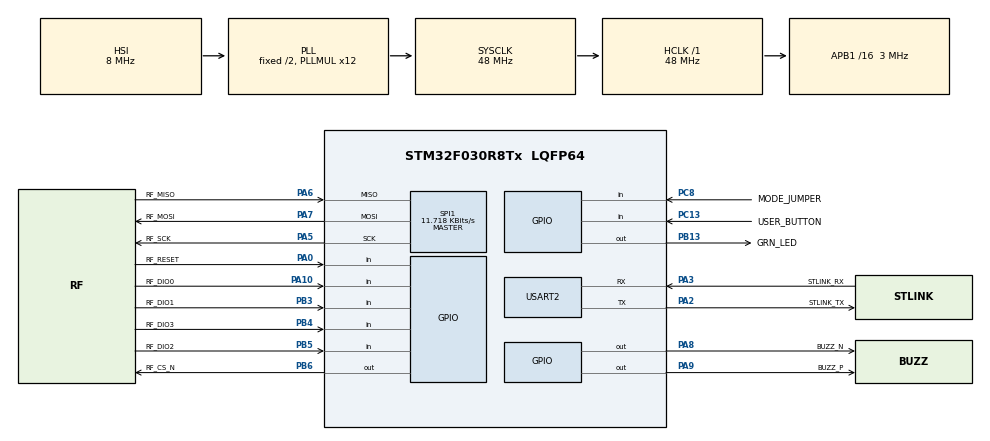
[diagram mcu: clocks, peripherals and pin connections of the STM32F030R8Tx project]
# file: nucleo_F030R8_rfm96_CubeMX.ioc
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Mcu.Family=STM32F0
Mcu.Name=STM32F030R8Tx
Mcu.Package=LQFP64
NVIC.SPI1_IRQn=true\:1\:0\:true\:true\:true\:2\:true\:true
NVIC.USART2_IRQn=true\:2\:0\:true\:true\:true\:1\:true\:true
PA0.GPIO_Label=RF_RESET
PA0.Signal=GPIO_Input
PA10.GPIO_Label=RF_DIO0
PA10.Signal=GPIO_Input
PA13.GPIO_Label=TMS
PA13.Signal=SYS_SWDIO
PA14.GPIO_Label=TCK
PA14.Signal=SYS_SWCLK
PA2.GPIO_Label=STLINK_TX
PA2.GPIO_Mode=GPIO_MODE_AF_PP
PA2.GPIO_PuPd=GPIO_NOPULL
PA2.GPIO_Speed=GPIO_SPEED_FREQ_LOW
PA2.Mode=Asynchronous
PA2.Signal=USART2_TX
PA3.GPIO_Label=STLINK_RX
PA3.GPIO_Mode=GPIO_MODE_AF_PP
PA3.GPIO_PuPd=GPIO_NOPULL
PA3.GPIO_Speed=GPIO_SPEED_FREQ_LOW
PA3.Mode=Asynchronous
PA3.Signal=USART2_RX
PA5.GPIO_Label=RF_SCK
PA5.Mode=Full_Duplex_Master
PA5.Signal=SPI1_SCK
PA6.GPIO_Label=RF_MISO
PA6.Mode=Full_Duplex_Master
PA6.Signal=SPI1_MISO
PA7.GPIO_Label=RF_MOSI
PA7.Mode=Full_Duplex_Master
PA7.Signal=SPI1_MOSI
PA8.GPIO_Label=BUZZ_N
PA8.Signal=GPIO_Output
PA9.GPIO_Label=BUZZ_P
PA9.Signal=GPIO_Output
PB13.GPIO_Label=GRN_LED
PB13.Signal=GPIO_Output
PB3.GPIO_Label=RF_DIO1
PB3.Signal=GPIO_Input
PB4.GPIO_Label=RF_DIO3
PB4.Signal=GPIO_Input
PB5.GPIO_Label=RF_DIO2
PB5.Signal=GPIO_Input
PB6.GPIO_Label=RF_CS_N
PB6.GPIO_Speed=GPIO_SPEED_FREQ_MEDIUM
PB6.PinState=GPIO_PIN_SET
PB6.Signal=GPIO_Output
PC13.GPIO_Label=USER_BUTTON
PC13.Signal=GPIO_Input
PC14-OSC32_IN.Mode=LSE-External-Oscillator
PC14-OSC32_IN.Signal=RCC_OSC32_IN
PC15-OSC32_OUT.Mode=LSE-External-Oscillator
PC15-OSC32_OUT.Signal=RCC_OSC32_OUT
PC8.GPIO_Label=MODE_JUMPER
PC8.GPIO_PuPd=GPIO_PULLUP
PC8.Signal=GPIO_Input
PF0-OSC_IN.Mode=HSE-External-Clock-Source
PF0-OSC_IN.Signal=RCC_OSC_IN
PF1-OSC_OUT.Signal=RCC_OSC_OUT
ProjectManager.HeapSize=0x200
ProjectManager.StackSize=0x400
ProjectManager.TargetToolchain=SW4STM32
RCC.AHBFreq_Value=48000000
RCC.APB1CLKDivider=RCC_HCLK_DIV16
RCC.APB1Freq_Value=3000000
RCC.APB1TimFreq_Value=6000000
RCC.HCLKFreq_Value=48000000
RCC.PLLMUL=RCC_PLL_MUL12
RCC.SYSCLKFreq_VALUE=48000000
RCC.SYSCLKSource=RCC_SYSCLKSOURCE_PLLCLK
SPI1.BaudRatePrescaler=SPI_BAUDRATEPRESCALER_256
SPI1.CalculateBaudRate=11.718 KBits/s
SPI1.DataSize=SPI_DATASIZE_8BIT
SPI1.Direction=SPI_DIRECTION_2LINES
SPI1.Mode=SPI_MODE_MASTER
SPI1.NSSPMode=SPI_NSS_PULSE_DISABLE
SPI1.VirtualType=VM_MASTER
USART2.VirtualMode-Asynchronous=VM_ASYNC
VP_RTC_VS_RTC_Activate.Mode=RTC_Enabled
board=NUCLEO-F030R8

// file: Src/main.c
/* USER CODE BEGIN Header */
/**
  ******************************************************************************
  * @file           : main.c
  * @brief          : Main program body
  ******************************************************************************
  * @attention
  *
  * <h2><center>&copy; Copyright (c) 2020 STMicroelectronics.
  * All rights reserved.</center></h2>
  *
  * This software component is licensed by ST under BSD 3-Clause license,
  * the "License"; You may not use this file except in compliance with the
  * License. You may obtain a copy of the License at:
  *                        opensource.org/licenses/BSD-3-Clause
  *
  ******************************************************************************
  */
/* USER CODE END Header */

#include "main.h"

/* USER CODE BEGIN Includes */

#include <string.h>
#include <stdio.h>
#include "RFM96.h"
#include "lcd.h"

/* USER CODE END Includes */

RTC_HandleTypeDef hrtc;

SPI_HandleTypeDef hspi1;

UART_HandleTypeDef huart2;

/* USER CODE BEGIN PV */
/* Private variables ---------------------------------------------------------*/

char msg[MSG_SIZE];
uint16_t msg_size;

/* USER CODE END PV */

void SystemClock_Config(void);
static void MX_GPIO_Init(void);
static void MX_USART2_UART_Init(void);
static void MX_RTC_Init(void);
static void MX_SPI1_Init(void);
static void MX_NVIC_Init(void);

static uint8_t tx_mode;
static uint8_t buffer[64];
static uint8_t toggle;
static uint8_t tx_count = 0;

/* USER CODE BEGIN PFP */
/* Private function prototypes -----------------------------------------------*/

/* USER CODE END PFP */

int main(void)
{

  /* MCU Configuration--------------------------------------------------------*/

  /* Reset of all peripherals, Initializes the Flash interface and the Systick. */
  HAL_Init();

  /* Configure the system clock */
  SystemClock_Config();

  /* Initialize all configured peripherals */
  MX_GPIO_Init();
  MX_USART2_UART_Init();
  MX_RTC_Init();
  MX_SPI1_Init();

  /* Initialize interrupts */
  MX_NVIC_Init();
  /* USER CODE BEGIN 2 */

  print("\r\nPOR");
  print("Build: " __DATE__ ", " __TIME__);
  beep(250,1);

  LCD_Init();
  LCD_ClearDisplay();
  LCD_ReturnHome();

  uint8_t c = 0x01;
  LCD_SetCGramAddress(0x00);
  for(uint8_t i=0; i<0x40; i++)
  {
      LCD_WriteData(c);
      c = c << 1;
      if (c == 0x20) c = 0x01;
   }
  LCD_SetDataAddress(0x00);
  for(uint8_t i=0; i<0x10; i++)
  {
      LCD_WriteData(i);
   }

//  uint8_t  c = 0;
//  for(uint8_t i=0; i<0x68; i++)
//  {
//      LCD_SetDataAddress(i);
//      LCD_WriteData(c);
//      ++c;
//      if (i == 0x13) i= 0x3F;
//      if (i == 0x53) i= 0x13;
//      if (i == 0x27) i= 0x53;
//  }

//
//  LCD_SetDataAddress(0x00);
//  LCD_WriteData('7');
//  LCD_WriteData('0');
//  LCD_WriteData(LCD_CHAR_DEGREE);
//  LCD_WriteData('F');
//
//  LCD_SetDataAddress(0x40);
//  LCD_WriteData('6');
//  LCD_WriteData('8');
//  LCD_WriteData(LCD_CHAR_DEGREE);
//  LCD_WriteData('F');
//
//  LCD_SetDataAddress(0x14);
//  LCD_WriteData('7');
//  LCD_WriteData('2');
//  LCD_WriteData(LCD_CHAR_DEGREE);
//  LCD_WriteData('F');

  while(1);

  RFM96_Init();

  tx_mode = (uint8_t) HAL_GPIO_ReadPin(MODE_JUMPER_GPIO_Port, MODE_JUMPER_Pin);
  print1("TX Mode", tx_mode);

  /* USER CODE END 2 */

  /* Infinite loop */
  /* USER CODE BEGIN WHILE */
  toggle = 0;

  if (tx_mode)
  {
	  // Tx Mode
	  while (1)
	  {
		  // turn on LED
		  HAL_GPIO_WritePin(GRN_LED_GPIO_Port, GRN_LED_Pin, GPIO_PIN_SET);

		  print1("--SEND--", tx_count);
		  ++tx_count;

		  RFM96_Send((uint8_t *) "0123456789ABCDEF", 16);

		  // turn off LED after 100ms (pulses = Tx mode)
		  Delay_ms(100);
		  HAL_GPIO_WritePin(GRN_LED_GPIO_Port, GRN_LED_Pin, GPIO_PIN_RESET);

		  // wait a full second
		  Delay_ms(900);

		  RFM96_ClearInt();

		/* USER CODE END WHILE */

		/* USER CODE BEGIN 3 */
	  }
  }
  else
  {
	  // Rx Mode
	  while(1)
	  {
		  print("--RECV--");
		  RFM96_Receive(buffer, 64);
		  printstr("data:", buffer);
	  }
  }
  /* USER CODE END 3 */
}

void SystemClock_Config(void)
{
  RCC_OscInitTypeDef RCC_OscInitStruct = {0};
  RCC_ClkInitTypeDef RCC_ClkInitStruct = {0};
  RCC_PeriphCLKInitTypeDef PeriphClkInit = {0};

  /** Initializes the CPU, AHB and APB busses clocks
  */
  RCC_OscInitStruct.OscillatorType = RCC_OSCILLATORTYPE_HSI|RCC_OSCILLATORTYPE_LSI;
  RCC_OscInitStruct.HSIState = RCC_HSI_ON;
  RCC_OscInitStruct.HSICalibrationValue = RCC_HSICALIBRATION_DEFAULT;
  RCC_OscInitStruct.LSIState = RCC_LSI_ON;
  RCC_OscInitStruct.PLL.PLLState = RCC_PLL_ON;
  RCC_OscInitStruct.PLL.PLLSource = RCC_PLLSOURCE_HSI;
  RCC_OscInitStruct.PLL.PLLMUL = RCC_PLL_MUL12;
  RCC_OscInitStruct.PLL.PREDIV = RCC_PREDIV_DIV1;
  if (HAL_RCC_OscConfig(&RCC_OscInitStruct) != HAL_OK)
  {
    Error_Handler();
  }
  /** Initializes the CPU, AHB and APB busses clocks
  */
  RCC_ClkInitStruct.ClockType = RCC_CLOCKTYPE_HCLK|RCC_CLOCKTYPE_SYSCLK
                              |RCC_CLOCKTYPE_PCLK1;
  RCC_ClkInitStruct.SYSCLKSource = RCC_SYSCLKSOURCE_PLLCLK;
  RCC_ClkInitStruct.AHBCLKDivider = RCC_SYSCLK_DIV1;
  RCC_ClkInitStruct.APB1CLKDivider = RCC_HCLK_DIV16;

  if (HAL_RCC_ClockConfig(&RCC_ClkInitStruct, FLASH_LATENCY_1) != HAL_OK)
  {
    Error_Handler();
  }
  PeriphClkInit.PeriphClockSelection = RCC_PERIPHCLK_RTC;
  PeriphClkInit.RTCClockSelection = RCC_RTCCLKSOURCE_LSI;
  if (HAL_RCCEx_PeriphCLKConfig(&PeriphClkInit) != HAL_OK)
  {
    Error_Handler();
  }
}

/**
  * @brief NVIC Configuration.
  * @retval None
  */
static void MX_NVIC_Init(void)
{
  /* USART2_IRQn interrupt configuration */
  HAL_NVIC_SetPriority(USART2_IRQn, 2, 0);
  HAL_NVIC_EnableIRQ(USART2_IRQn);
  /* SPI1_IRQn interrupt configuration */
  HAL_NVIC_SetPriority(SPI1_IRQn, 1, 0);
  HAL_NVIC_EnableIRQ(SPI1_IRQn);
}

static void MX_RTC_Init(void)
{

  /** Initialize RTC Only
  */
  hrtc.Instance = RTC;
  hrtc.Init.HourFormat = RTC_HOURFORMAT_24;
  hrtc.Init.AsynchPrediv = 127;
  hrtc.Init.SynchPrediv = 255;
  hrtc.Init.OutPut = RTC_OUTPUT_DISABLE;
  hrtc.Init.OutPutPolarity = RTC_OUTPUT_POLARITY_HIGH;
  hrtc.Init.OutPutType = RTC_OUTPUT_TYPE_OPENDRAIN;
  if (HAL_RTC_Init(&hrtc) != HAL_OK)
  {
    Error_Handler();
  }

}

static void MX_SPI1_Init(void)
{

  /* SPI1 parameter configuration*/
  hspi1.Instance = SPI1;
  hspi1.Init.Mode = SPI_MODE_MASTER;
  hspi1.Init.Direction = SPI_DIRECTION_2LINES;
  hspi1.Init.DataSize = SPI_DATASIZE_8BIT;
  hspi1.Init.CLKPolarity = SPI_POLARITY_LOW;
  hspi1.Init.CLKPhase = SPI_PHASE_1EDGE;
  hspi1.Init.NSS = SPI_NSS_SOFT;
  hspi1.Init.BaudRatePrescaler = SPI_BAUDRATEPRESCALER_256;
  hspi1.Init.FirstBit = SPI_FIRSTBIT_MSB;
  hspi1.Init.TIMode = SPI_TIMODE_DISABLE;
  hspi1.Init.CRCCalculation = SPI_CRCCALCULATION_DISABLE;
  hspi1.Init.CRCPolynomial = 7;
  hspi1.Init.CRCLength = SPI_CRC_LENGTH_DATASIZE;
  hspi1.Init.NSSPMode = SPI_NSS_PULSE_DISABLE;
  if (HAL_SPI_Init(&hspi1) != HAL_OK)
  {
    Error_Handler();
  }

}

static void MX_USART2_UART_Init(void)
{

  huart2.Instance = USART2;
  huart2.Init.BaudRate = 38400;
  huart2.Init.WordLength = UART_WORDLENGTH_8B;
  huart2.Init.StopBits = UART_STOPBITS_1;
  huart2.Init.Parity = UART_PARITY_NONE;
  huart2.Init.Mode = UART_MODE_TX_RX;
  huart2.Init.HwFlowCtl = UART_HWCONTROL_NONE;
  huart2.Init.OverSampling = UART_OVERSAMPLING_16;
  huart2.Init.OneBitSampling = UART_ONE_BIT_SAMPLE_DISABLE;
  huart2.AdvancedInit.AdvFeatureInit = UART_ADVFEATURE_NO_INIT;
  if (HAL_UART_Init(&huart2) != HAL_OK)
  {
    Error_Handler();
  }

}

static void MX_GPIO_Init(void)
{
  GPIO_InitTypeDef GPIO_InitStruct = {0};

  /* GPIO Ports Clock Enable */
  __HAL_RCC_GPIOC_CLK_ENABLE();
  __HAL_RCC_GPIOF_CLK_ENABLE();
  __HAL_RCC_GPIOA_CLK_ENABLE();
  __HAL_RCC_GPIOB_CLK_ENABLE();

  /*Configure GPIO pin Output Level */
  HAL_GPIO_WritePin(GPIOF, LCD_RS_Pin|LCD_RW_Pin, GPIO_PIN_RESET);

  /*Configure GPIO pin Output Level */
  HAL_GPIO_WritePin(GPIOC, LCD_E_Pin|GRN_LED_Pin, GPIO_PIN_RESET);

  /*Configure GPIO pin Output Level */
  HAL_GPIO_WritePin(GPIOB, LCD_DB7_Pin|LCD_DB4_Pin|LCD_DB5_Pin|LCD_DB6_Pin, GPIO_PIN_RESET);

  /*Configure GPIO pin Output Level */
  HAL_GPIO_WritePin(GPIOA, BUZZ_N_Pin|BUZZ_P_Pin, GPIO_PIN_RESET);

  /*Configure GPIO pin Output Level */
  HAL_GPIO_WritePin(RF_CS_N_GPIO_Port, RF_CS_N_Pin, GPIO_PIN_SET);

  /*Configure GPIO pin : USER_BUTTON_Pin */
  GPIO_InitStruct.Pin = USER_BUTTON_Pin;
  GPIO_InitStruct.Mode = GPIO_MODE_INPUT;
  GPIO_InitStruct.Pull = GPIO_NOPULL;
  HAL_GPIO_Init(USER_BUTTON_GPIO_Port, &GPIO_InitStruct);

  /*Configure GPIO pins : RF_RESET_Pin RF_DIO0_Pin */
  GPIO_InitStruct.Pin = RF_RESET_Pin|RF_DIO0_Pin;
  GPIO_InitStruct.Mode = GPIO_MODE_INPUT;
  GPIO_InitStruct.Pull = GPIO_NOPULL;
  HAL_GPIO_Init(GPIOA, &GPIO_InitStruct);

  /*Configure GPIO pins : LCD_RS_Pin LCD_RW_Pin */
  GPIO_InitStruct.Pin = LCD_RS_Pin|LCD_RW_Pin;
  GPIO_InitStruct.Mode = GPIO_MODE_OUTPUT_PP;
  GPIO_InitStruct.Pull = GPIO_NOPULL;
  GPIO_InitStruct.Speed = GPIO_SPEED_FREQ_LOW;
  HAL_GPIO_Init(GPIOF, &GPIO_InitStruct);

  /*Configure GPIO pins : LCD_E_Pin GRN_LED_Pin */
  GPIO_InitStruct.Pin = LCD_E_Pin|GRN_LED_Pin;
  GPIO_InitStruct.Mode = GPIO_MODE_OUTPUT_PP;
  GPIO_InitStruct.Pull = GPIO_NOPULL;
  GPIO_InitStruct.Speed = GPIO_SPEED_FREQ_LOW;
  HAL_GPIO_Init(GPIOC, &GPIO_InitStruct);

  /*Configure GPIO pins : LCD_DB7_Pin LCD_DB4_Pin LCD_DB5_Pin LCD_DB6_Pin */
  GPIO_InitStruct.Pin = LCD_DB7_Pin|LCD_DB4_Pin|LCD_DB5_Pin|LCD_DB6_Pin;
  GPIO_InitStruct.Mode = GPIO_MODE_OUTPUT_PP;
  GPIO_InitStruct.Pull = GPIO_NOPULL;
  GPIO_InitStruct.Speed = GPIO_SPEED_FREQ_LOW;
  HAL_GPIO_Init(GPIOB, &GPIO_InitStruct);

  /*Configure GPIO pin : MODE_JUMPER_Pin */
  GPIO_InitStruct.Pin = MODE_JUMPER_Pin;
  GPIO_InitStruct.Mode = GPIO_MODE_INPUT;
  GPIO_InitStruct.Pull = GPIO_PULLUP;
  HAL_GPIO_Init(MODE_JUMPER_GPIO_Port, &GPIO_InitStruct);

  /*Configure GPIO pins : BUZZ_N_Pin BUZZ_P_Pin */
  GPIO_InitStruct.Pin = BUZZ_N_Pin|BUZZ_P_Pin;
  GPIO_InitStruct.Mode = GPIO_MODE_OUTPUT_PP;
  GPIO_InitStruct.Pull = GPIO_NOPULL;
  GPIO_InitStruct.Speed = GPIO_SPEED_FREQ_LOW;
  HAL_GPIO_Init(GPIOA, &GPIO_InitStruct);

  /*Configure GPIO pins : RF_DIO1_Pin RF_DIO3_Pin RF_DIO2_Pin */
  GPIO_InitStruct.Pin = RF_DIO1_Pin|RF_DIO3_Pin|RF_DIO2_Pin;
  GPIO_InitStruct.Mode = GPIO_MODE_INPUT;
  GPIO_InitStruct.Pull = GPIO_NOPULL;
  HAL_GPIO_Init(GPIOB, &GPIO_InitStruct);

  /*Configure GPIO pin : RF_CS_N_Pin */
  GPIO_InitStruct.Pin = RF_CS_N_Pin;
  GPIO_InitStruct.Mode = GPIO_MODE_OUTPUT_PP;
  GPIO_InitStruct.Pull = GPIO_NOPULL;
  GPIO_InitStruct.Speed = GPIO_SPEED_FREQ_MEDIUM;
  HAL_GPIO_Init(RF_CS_N_GPIO_Port, &GPIO_InitStruct);

}

/* USER CODE BEGIN 4 */

void print(const char *text)
{
	  sprintf(msg, "%s\r\n", text );
	  msg_size = strlen(msg);
	  HAL_UART_Transmit(&huart2, (uint8_t *) msg, msg_size, TIMEOUT_1_SEC);
}

void print1(const char *text, uint8_t x)
{
	  sprintf(msg, "%s 0x%02X\r\n", text, (int) x );
	  msg_size = strlen(msg);
	  HAL_UART_Transmit(&huart2, (uint8_t *) msg, msg_size, TIMEOUT_1_SEC);
}

void print2(const char *text, uint8_t x, uint8_t y)
{
	  sprintf(msg, "%s 0x%02X 0x%02X\r\n", text, (int) x, (int) y );
	  msg_size = strlen(msg);
	  HAL_UART_Transmit(&huart2, (uint8_t *) msg, msg_size, TIMEOUT_1_SEC);
}

void printstr(const char *text, uint8_t * data)
{
	  sprintf(msg, "%s: %s\r\n", text, (char *) data );
	  msg_size = strlen(msg);
	  HAL_UART_Transmit(&huart2, (uint8_t *) msg, msg_size, TIMEOUT_1_SEC);
}

void printhex(uint8_t x)
{
      sprintf(msg, "%02X", (int) x );
      msg_size = strlen(msg);
      HAL_UART_Transmit(&huart2, (uint8_t *) msg, msg_size, TIMEOUT_1_SEC);
}

/* set pitch to 0,1,2,3 with 0 highest pitch */
void beep(uint32_t duration_ms, uint8_t pitch)
{
	uint32_t tick;

	uint32_t mask = (1 << pitch);

	uint32_t start = HAL_GetTick();
	do {
		tick = HAL_GetTick();
		if (tick & mask)
		{
			// Piezo/Speaker positive voltage
			HAL_GPIO_WritePin(BUZZ_P_GPIO_Port, BUZZ_P_Pin, GPIO_PIN_SET);
			HAL_GPIO_WritePin(BUZZ_N_GPIO_Port, BUZZ_N_Pin, GPIO_PIN_RESET);
		}
		else
		{
			// Piezo/Speaker negative voltage
			HAL_GPIO_WritePin(BUZZ_P_GPIO_Port, BUZZ_P_Pin, GPIO_PIN_RESET);
			HAL_GPIO_WritePin(BUZZ_N_GPIO_Port, BUZZ_N_Pin, GPIO_PIN_SET);
		}
	} while ((tick - start) < duration_ms);

	// Peizo/Speaker zero voltage
	HAL_GPIO_WritePin(BUZZ_P_GPIO_Port, BUZZ_P_Pin, GPIO_PIN_RESET);
	HAL_GPIO_WritePin(BUZZ_N_GPIO_Port, BUZZ_N_Pin, GPIO_PIN_RESET);

	return;
}

void Delay_ms(uint32_t delay_ms)
{
    /**
     * This should correctly handle SysTic roll-overs.
     * See:
     *   https://stackoverflow.com/questions/61443/rollover-safe-timer-tick-comparisons
     */
    uint32_t start_time_ms = HAL_GetTick();
    while ( (HAL_GetTick() - start_time_ms) < delay_ms)
    {
        // spin wait
    }

    return;
}
/* USER CODE END 4 */

void Error_Handler(void)
{
  while(1)
  {
  }
}

/************************ (C) COPYRIGHT STMicroelectronics *****END OF FILE****/
